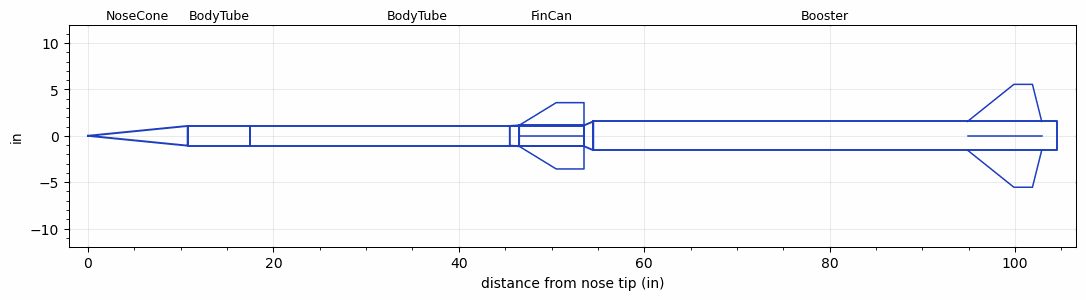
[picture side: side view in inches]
<RASAeroDocument>
 <FileVersion>2</FileVersion>
 <RocketDesign>
  <NoseCone>
   <Length>10.75</Length>
   <Diameter>2.125</Diameter>
   <Shape>Conical</Shape>
   <BluntRadius>0.0625</BluntRadius>
   <Location>0</Location>
  </NoseCone>
  <BodyTube>
   <Length>6.75</Length>
   <Diameter>2.125</Diameter>
   <Location>10.75</Location>
  </BodyTube>
  <BodyTube>
   <Length>36</Length>
   <Diameter>2.125</Diameter>
   <Location>17.5</Location>
  </BodyTube>
  <FinCan>
   <Length>7</Length>
   <Diameter>2.25</Diameter>
   <InsideDiameter>2.125</InsideDiameter>
   <Location>53.5</Location>
   <ShoulderLength>1</ShoulderLength>
   <Offset>-7</Offset>
   <Fin>
    <Count>4</Count>
    <Chord>7</Chord>
    <Span>2.45</Span>
    <SweepDistance>4</SweepDistance>
    <TipChord>3</TipChord>
    <Thickness>0.125</Thickness>
    <LERadius>0.02</LERadius>
    <Location>7</Location>
    <AirfoilSection>Hexagonal</AirfoilSection>
    <FX1>1</FX1>
    <FX3>0.5</FX3>
   </Fin>
  </FinCan>
  <Booster>
   <Length>50</Length>
   <Diameter>3.1</Diameter>
   <InsideDiameter>2.25</InsideDiameter>
   <Location>53.5</Location>
   <ShoulderLength>1</ShoulderLength>
   <Fin>
    <Count>4</Count>
    <Chord>8</Chord>
    <Span>4</Span>
    <SweepDistance>5</SweepDistance>
    <TipChord>2</TipChord>
    <Thickness>0.125</Thickness>
    <LERadius>0.005</LERadius>
    <Location>9.625</Location>
    <AirfoilSection>Hexagonal Blunt Base</AirfoilSection>
    <FX1>0.75</FX1>
   </Fin>
  </Booster>
  <Surface>Camouflage Paint</Surface>
  <ModifiedBarrowman>True</ModifiedBarrowman>
  <Turbulence>True</Turbulence>
  <UseBooster1>False</UseBooster1>
  <UseBooster2>False</UseBooster2>
 </RocketDesign>
 <LaunchSite>
  <Altitude>4000</Altitude>
  <Pressure>0</Pressure>
  <RodAngle>2</RodAngle>
  <RodLength>20</RodLength>
  <Temperature>85</Temperature>
  <WindSpeed>7</WindSpeed>
 </LaunchSite>
 <Recovery>
  <Altitude1>1000</Altitude1>
  <Altitude2>1000</Altitude2>
  <DeviceType1>None</DeviceType1>
  <DeviceType2>None</DeviceType2>
  <Event1>False</Event1>
  <Event2>False</Event2>
  <Size1>1</Size1>
  <Size2>1</Size2>
  <EventType1>None</EventType1>
  <EventType2>None</EventType2>
  <CD1>1.33</CD1>
  <CD2>1.33</CD2>
 </Recovery>
 <SimulationList>
  <Simulation>
   <SustainerEngine>L1977  (bepisbad)</SustainerEngine>
   <SustainerLaunchWt>10</SustainerLaunchWt>
   <SustainerNozzleDiameter>1.9</SustainerNozzleDiameter>
   <SustainerCG>31</SustainerCG>
   <SustainerIgnitionDelay>10</SustainerIgnitionDelay>
   <Booster1Engine>N2651  (bps)</Booster1Engine>
   <Booster1LaunchWt>28</Booster1LaunchWt>
   <Booster1SeparationDelay>0</Booster1SeparationDelay>
   <Booster1IgnitionDelay>0</Booster1IgnitionDelay>
   <Booster1CG>60</Booster1CG>
   <Booster1NozzleDiameter>2.9</Booster1NozzleDiameter>
   <IncludeBooster1>True</IncludeBooster1>
   <Booster2Delay>0</Booster2Delay>
   <IncludeBooster2>False</IncludeBooster2>
   <TimetoApogee>145.7114</TimetoApogee>
   <MaxAltitude>309116.7</MaxAltitude>
   <MaxVelocity>5619.086</MaxVelocity>
  </Simulation>
 </SimulationList>
</RASAeroDocument>
